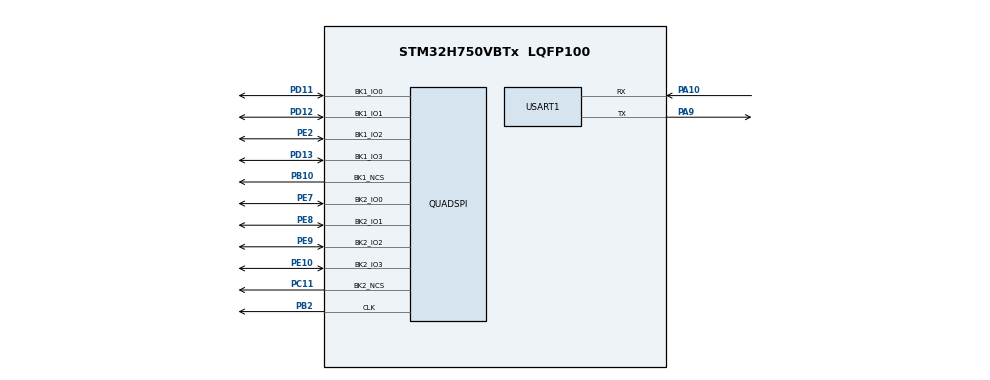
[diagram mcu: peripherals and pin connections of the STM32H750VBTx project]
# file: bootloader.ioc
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CORTEX_M7.default_mode_Activation=0
Mcu.Family=STM32H7
Mcu.Name=STM32H750VBTx
Mcu.Package=LQFP100
NVIC.PriorityGroup=NVIC_PRIORITYGROUP_4
PA10.Mode=Asynchronous
PA10.Signal=USART1_RX
PA13\ (JTMS/SWDIO).Mode=Serial_Wire
PA13\ (JTMS/SWDIO).Signal=DEBUG_JTMS-SWDIO
PA14\ (JTCK/SWCLK).Mode=Serial_Wire
PA14\ (JTCK/SWCLK).Signal=DEBUG_JTCK-SWCLK
PA9.Mode=Asynchronous
PA9.Signal=USART1_TX
PB10.Mode=Enable Chip Select for each bank
PB10.Signal=QUADSPI_BK1_NCS
PB2.Mode=Dual_Bank
PB2.Signal=QUADSPI_CLK
PC11.Mode=Enable Chip Select for each bank
PC11.Signal=QUADSPI_BK2_NCS
PD11.Mode=Dual_Bank
PD11.Signal=QUADSPI_BK1_IO0
PD12.Mode=Dual_Bank
PD12.Signal=QUADSPI_BK1_IO1
PD13.Mode=Dual_Bank
PD13.Signal=QUADSPI_BK1_IO3
PE10.Mode=Dual_Bank
PE10.Signal=QUADSPI_BK2_IO3
PE2.Mode=Dual_Bank
PE2.Signal=QUADSPI_BK1_IO2
PE7.Mode=Dual_Bank
PE7.Signal=QUADSPI_BK2_IO0
PE8.Mode=Dual_Bank
PE8.Signal=QUADSPI_BK2_IO1
PE9.Mode=Dual_Bank
PE9.Signal=QUADSPI_BK2_IO2
ProjectManager.HeapSize=0x200
ProjectManager.StackSize=0x800
ProjectManager.TargetToolchain=MDK-ARM V5.32
QUADSPI.ChipSelectHighTime=QSPI_CS_HIGH_TIME_2_CYCLE
QUADSPI.ClockPrescaler=0
QUADSPI.FifoThreshold=4
QUADSPI.FlashSize=23
QUADSPI.SampleShifting=QSPI_SAMPLE_SHIFTING_HALFCYCLE
RCC.ADCFreq_Value=129000000
RCC.APB1Freq_Value=32000000
RCC.APB2Freq_Value=32000000
RCC.APB3Freq_Value=32000000
RCC.APB4Freq_Value=32000000
RCC.CortexFreq_Value=64000000
RCC.D1PPRE=RCC_APB3_DIV2
RCC.D2PPRE1=RCC_APB1_DIV2
RCC.D2PPRE2=RCC_APB2_DIV2
RCC.D3PPRE=RCC_APB4_DIV2
RCC.HCLKFreq_Value=64000000
RCC.SYSCLKFreq_VALUE=64000000
RCC.USBFreq_Value=129000000
USART1.VirtualMode-Asynchronous=VM_ASYNC
board=custom

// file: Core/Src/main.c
/* USER CODE BEGIN Header */
/**
  ******************************************************************************
  * @file           : main.c
  * @brief          : Main program body for STM32H750VB QSPI Dual-Slot Bootloader
  ******************************************************************************
  * @attention
  *
  * Copyright (c) 2023 STMicroelectronics.
  * All rights reserved.
  *
  ******************************************************************************
  */
/* USER CODE END Header */
#include "main.h"
#include "quadspi.h"
#include "usart.h"
#include "gpio.h"

/* USER CODE BEGIN Includes */
#include <stdio.h>
#include <string.h>
#include "bsp_rgb.h"
#include "bsp_qspi_w25q.h"
#include "bsp_mpu.h"
#include "bootloader.h"
#include "boot_cli.h"
#include "ymodem.h"
/* USER CODE END Includes */

void SystemClock_Config(void);

int main(void)
{

  /* MCU Configuration--------------------------------------------------------*/

  /* Reset of all peripherals, Initializes the Flash interface and the Systick. */
  HAL_Init();

  /* Configure the system clock */
  SystemClock_Config();

  /* Initialize all configured peripherals */
  MX_GPIO_Init();
  MX_QUADSPI_Init();
  MX_USART1_UART_Init();
  /* USER CODE BEGIN 2 */

  /* 1. Initialize Onboard RGB LED indicator */
  BSP_RGB_Init();
  BSP_RGB_SetColor(RGB_COLOR_BLUE); // Blue: Bootloader running / Self-test

  /* 2. Output Professional Startup Banner */
  Bootloader_PrintBanner();

  /* 3. Configure MPU & L1 Instruction Cache Acceleration */
  BSP_MPU_Config();
  BSP_Cache_Enable();

  /* 4. Step 1: Clean reset QSPI peripheral state machine and software-reset Flash */
  printf(" [STEP 1/5] Initializing QSPI Controller & Flash Software Reset...\r\n");
  if (BSP_W25Qx_Init() != W25Q_OK)
  {
    Bootloader_Panic("Failed to initialize QSPI / Reset Flash!");
  }
  printf(" [OK]       QSPI Peripheral & Flash Reset Succeeded.\r\n\r\n");

  /* 5. Step 2: Probe Flash ID and JEDEC Information */
  printf(" [STEP 2/5] Probing Flash Hardware Identity...\r\n");
  uint8_t mf_id = 0;
  uint8_t dev_id = 0;
  uint32_t jedec_id = 0;

  if (BSP_W25Qx_ReadID(&mf_id, &dev_id) != W25Q_OK)
  {
    Bootloader_Panic("Failed to read Flash Device ID (Command 0x90)!");
  }
  BSP_W25Qx_ReadJEDECID(&jedec_id);

  printf(" [OK]       Manufacturer ID : 0x%02X (Winbond)\r\n", mf_id);
  printf("            Device ID       : 0x%02X (W25Q64 64M-bit / 8M-Byte)\r\n", dev_id);
  printf("            JEDEC ID        : 0x%06lX\r\n\r\n", (unsigned long)jedec_id);

  /* 6. Step 3: Check and Ensure Quad Enable (QE) Bit */
  printf(" [STEP 3/5] Checking Quad Enable (QE) Status in Flash...\r\n");
  if (BSP_W25Qx_CheckAndEnableQE() != W25Q_OK)
  {
    Bootloader_Panic("Quad Enable (QE) bit configuration failed!");
  }
  printf("\r\n");

  /* 7. Step 4: Load NV-Config Parameters and Check Integrity */
  printf(" [STEP 4/5] Loading Persistent NV-Config Parameters...\r\n");
  Bootloader_Config_Init();
  BootConfig_t *pCfg = Bootloader_Config_Get();

  /* Check health of current active slot */
  uint32_t sp = 0, pc = 0;
  BootStatus_t status = Bootloader_VerifySlot((BootSlot_t)pCfg->active_slot, &sp, &pc);

  if (status != BOOT_OK || (pCfg->upgrade_state == UPGRADE_STATE_TESTING && pCfg->boot_count >= pCfg->max_boot_count))
  {
    if (status != BOOT_OK)
    {
      printf(" [WARN] Active slot image corrupted!\r\n");
    }
    else
    {
      printf(" [WARN] Tentative OTA boot attempts limit reached (%u >= %u). Initiating Rollback...\r\n",
             pCfg->boot_count, pCfg->max_boot_count);
    }

    /* Try automated rollback from backup slot */
    if (Bootloader_Rollback() == 0)
    {
      /* Re-verify after rollback */
      status = Bootloader_VerifySlot((BootSlot_t)pCfg->active_slot, &sp, &pc);
    }
  }
  else
  {
    /* 仅在待确认的 OTA 升级模式下累加试运行计数，日常开发保持 0 避免误触发回滚 */
    if (pCfg->upgrade_state == UPGRADE_STATE_TESTING)
    {
      pCfg->boot_count++;
      Bootloader_Config_Save();
    }
    else if (pCfg->boot_count != 0)
    {
      pCfg->boot_count = 0;
      Bootloader_Config_Save();
    }
  }
  printf("\r\n");

  /* 8. Intercept Check: Allow User to Enter Interactive Console (CLI) or Ymodem IAP */
  if (Boot_CLI_CheckIntercept(2))
  {
    Boot_CLI_Run();
  }

  /* 9. Step 5: Activate 4-Line Memory Mapped Mode (0xEB Fast Read Quad I/O) */
  printf(" [STEP 5/5] Activating 4-Line Memory Mapped Mode (0xEB)...\r\n");

  /* Reset QSPI hardware state machine and soft-reset Flash chip to exit indirect command mode cleanly */
  QUADSPI->CCR = 0;
  QUADSPI->CR &= ~QUADSPI_CR_EN;
  MX_QUADSPI_Init();
  BSP_W25Qx_Reset();

  if (BSP_W25Qx_EnableMemoryMappedMode() != W25Q_OK)
  {
    Bootloader_Panic("Failed to activate QSPI Memory Mapped Mode!");
  }
  printf(" [OK]       Memory Mapped Mode Enabled (Mapped @ 0x%08lX).\r\n\r\n", QSPI_BASE_ADDR);

  /* 10. Verify Application Vector Table and Safely Jump to Active Slot */
  uint32_t targetAddr = (pCfg->active_slot == BOOT_SLOT_A) ? SLOT_A_ADDR : SLOT_B_ADDR;
  Bootloader_JumpToApp(targetAddr);

  /* USER CODE END 2 */

  /* Infinite loop */
  while (1)
  {

  }
}

void SystemClock_Config(void)
{
  RCC_OscInitTypeDef RCC_OscInitStruct = {0};
  RCC_ClkInitTypeDef RCC_ClkInitStruct = {0};

  /** Supply configuration update enable */
  HAL_PWREx_ConfigSupply(PWR_LDO_SUPPLY);

  /** Configure the main internal regulator output voltage: Scale 1 for 400MHz */
  __HAL_PWR_VOLTAGESCALING_CONFIG(PWR_REGULATOR_VOLTAGE_SCALE1);

  while(!__HAL_PWR_GET_FLAG(PWR_FLAG_VOSRDY)) {}

  /** Initializes the RCC Oscillators: HSI (64MHz) with PLL1 enabled
    * VCO = (64MHz / 4) * 50 = 800MHz
    * SYSCLK = 800MHz / 2 = 400MHz
    */
  RCC_OscInitStruct.OscillatorType = RCC_OSCILLATORTYPE_HSI;
  RCC_OscInitStruct.HSIState = RCC_HSI_DIV1;
  RCC_OscInitStruct.HSICalibrationValue = RCC_HSICALIBRATION_DEFAULT;
  RCC_OscInitStruct.PLL.PLLState = RCC_PLL_ON;
  RCC_OscInitStruct.PLL.PLLSource = RCC_PLLSOURCE_HSI;
  RCC_OscInitStruct.PLL.PLLM = 4;
  RCC_OscInitStruct.PLL.PLLN = 50;
  RCC_OscInitStruct.PLL.PLLP = 2;
  RCC_OscInitStruct.PLL.PLLQ = 4;
  RCC_OscInitStruct.PLL.PLLR = 2;
  RCC_OscInitStruct.PLL.PLLRGE = RCC_PLL1VCIRANGE_3;
  RCC_OscInitStruct.PLL.PLLVCOSEL = RCC_PLL1VCOWIDE;
  RCC_OscInitStruct.PLL.PLLFRACN = 0;
  if (HAL_RCC_OscConfig(&RCC_OscInitStruct) != HAL_OK)
  {
    Error_Handler();
  }

  /** Initializes the CPU, AHB and APB buses clocks:
    * SYSCLK = 400MHz, HCLK = 200MHz, APB1/2/3/4 = 100MHz
    */
  RCC_ClkInitStruct.ClockType = RCC_CLOCKTYPE_HCLK|RCC_CLOCKTYPE_SYSCLK
                              |RCC_CLOCKTYPE_PCLK1|RCC_CLOCKTYPE_PCLK2
                              |RCC_CLOCKTYPE_D3PCLK1|RCC_CLOCKTYPE_D1PCLK1;
  RCC_ClkInitStruct.SYSCLKSource = RCC_SYSCLKSOURCE_PLLCLK;
  RCC_ClkInitStruct.SYSCLKDivider = RCC_SYSCLK_DIV1;
  RCC_ClkInitStruct.AHBCLKDivider = RCC_HCLK_DIV2;
  RCC_ClkInitStruct.APB3CLKDivider = RCC_APB3_DIV2;
  RCC_ClkInitStruct.APB1CLKDivider = RCC_APB1_DIV2;
  RCC_ClkInitStruct.APB2CLKDivider = RCC_APB2_DIV2;
  RCC_ClkInitStruct.APB4CLKDivider = RCC_APB4_DIV2;

  if (HAL_RCC_ClockConfig(&RCC_ClkInitStruct, FLASH_LATENCY_4) != HAL_OK)
  {
    Error_Handler();
  }
}

void Error_Handler(void)
{
  __disable_irq();
  while (1)
  {
  }
}
